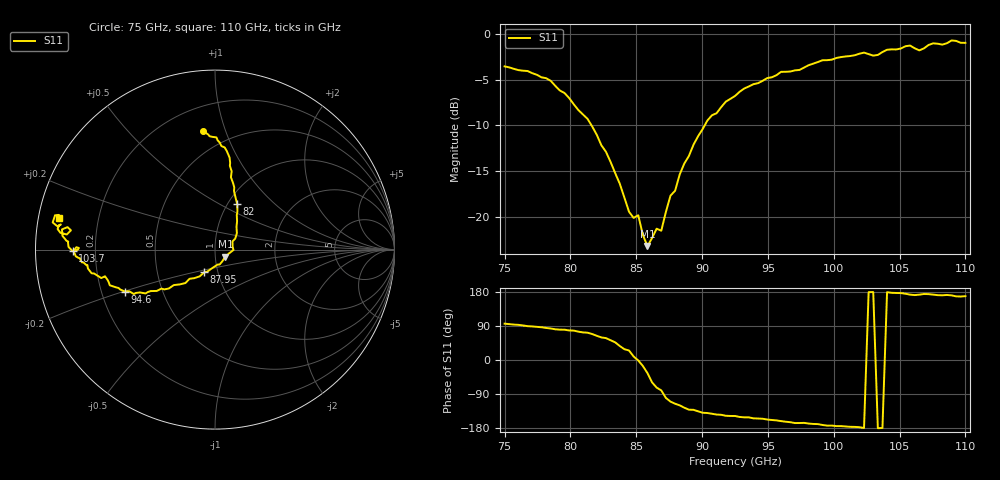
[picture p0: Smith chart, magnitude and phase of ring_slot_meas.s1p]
! Created with skrf 1.8.0 (http://scikit-rf.org).
# GHz S RI R 50.0
!freq ReS11 ImS11
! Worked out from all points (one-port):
!   101 points, 75 GHz to 110 GHz, reference 50 ohm
!   lowest |S11| = -23.1 dB at 85.85 GHz (marker M1), VSWR 1.15, Z = 55.9 - j4.45 ohm
!   |S11| at or under -10 dB: 81.61 GHz to 90.19 GHz (8.587 GHz wide, 10 % of centre)
!   S11 on the Smith chart (normalised r, x): 75 GHz: 0.36, +0.84; 82 GHz: 1.11, +0.61; 87.95 GHz: 0.86, -0.22; 94.6 GHz: 0.30, -0.20; 103.7 GHz: 0.12, -0.01; 110 GHz: 0.06, +0.10
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75  -0.0677 0.6592
78.15  0.0538 0.5692
79.55  0.0828 0.4676
82  0.124 0.2527
83.75  0.122 0.0914
84.45  0.0973 0.0455
85.15  0.1028 -0.00213
85.85  0.0575 -0.0396
86.55  0.0256 -0.0831
86.9  0.0144 -0.0835
87.6  -0.0446 -0.1237
87.95  -0.0599 -0.1262
88.3  -0.0849 -0.1489
90.4  -0.2572 -0.2167
92.5  -0.387 -0.2442
94.6  -0.5016 -0.2336
97.05  -0.6127 -0.1486
97.75  -0.6336 -0.1585
99.15  -0.7079 -0.1054
101.25  -0.7529 -0.0483
102.65  -0.7727 0.0133
103.7  -0.7929 -0.00869
105.8  -0.8526 0.1127
106.5  -0.8027 0.1073
107.55  -0.8768 0.1148
108.6  -0.8764 0.1286
109.3  -0.8913 0.191
110  -0.8718 0.1774
